VERSION 5.7 ;
BUSBITCHARS "[]" ;
DIVIDERCHAR "/" ;

PROPERTYDEFINITIONS
  MACRO CatenaDesignType STRING ;
END PROPERTYDEFINITIONS

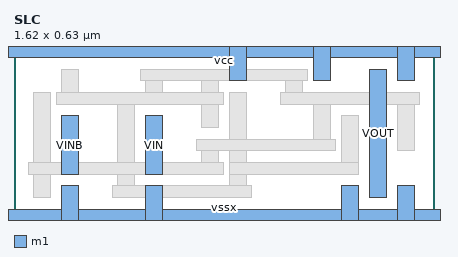
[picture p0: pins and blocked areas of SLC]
MACRO SLC
  CLASS CORE ;
  ORIGIN 0 0 ;
  FOREIGN SLC 0 0 ;
  SIZE 1.62 BY 0.63 ;
  SYMMETRY X Y ;
  SITE CoreSite ;
  PIN vssx
    DIRECTION INOUT ;
    USE GROUND ;
    SHAPE ABUTMENT ;
    PORT
      LAYER m1 ;
        RECT -0.034 -0.022 1.654 0.022 ;
        RECT 1.478 -0.022 1.546 0.112 ;
        RECT 1.262 -0.022 1.33 0.112 ;
        RECT 0.506 -0.022 0.574 0.112 ;
        RECT 0.182 -0.022 0.25 0.112 ;
    END
  END vssx
  PIN vcc
    DIRECTION INOUT ;
    USE POWER ;
    SHAPE ABUTMENT ;
    PORT
      LAYER m1 ;
        RECT -0.034 0.608 1.654 0.652 ;
        RECT 1.478 0.518 1.546 0.652 ;
        RECT 1.154 0.518 1.222 0.652 ;
        RECT 0.83 0.518 0.898 0.652 ;
    END
  END vcc
  PIN VOUT
    DIRECTION OUTPUT ;
    USE SIGNAL ;
    PORT
      LAYER m1 ;
        RECT 1.37 0.068 1.438 0.562 ;
    END
  END VOUT
  PIN VINB
    DIRECTION INPUT ;
    USE ANALOG ;
    PORT
      LAYER m1 ;
        RECT 0.182 0.158 0.25 0.382 ;
    END
  END VINB
  PIN VIN
    DIRECTION INPUT ;
    USE ANALOG ;
    PORT
      LAYER m1 ;
        RECT 0.506 0.158 0.574 0.382 ;
    END
  END VIN
  OBS
    LAYER m1 ;
      RECT 0.83 0.068 0.898 0.472 ;
      RECT 1.262 0.158 1.33 0.382 ;
      RECT 0.83 0.158 1.33 0.202 ;
      RECT 1.478 0.248 1.546 0.472 ;
      RECT 1.154 0.248 1.222 0.472 ;
      RECT 1.046 0.428 1.114 0.562 ;
      RECT 0.722 0.158 0.79 0.292 ;
      RECT 0.722 0.338 0.79 0.562 ;
      RECT 0.506 0.428 0.574 0.562 ;
      RECT 0.398 0.068 0.466 0.472 ;
      RECT 0.182 0.428 0.25 0.562 ;
      RECT 0.074 0.068 0.142 0.472 ;
    LAYER v1 ;
      RECT 1.482 0.428 1.542 0.472 ;
      RECT 1.158 0.248 1.218 0.292 ;
      RECT 1.05 0.428 1.11 0.472 ;
      RECT 1.05 0.518 1.11 0.562 ;
      RECT 0.834 0.068 0.894 0.112 ;
      RECT 0.726 0.158 0.786 0.202 ;
      RECT 0.726 0.248 0.786 0.292 ;
      RECT 0.726 0.428 0.786 0.472 ;
      RECT 0.51 0.518 0.57 0.562 ;
      RECT 0.402 0.068 0.462 0.112 ;
      RECT 0.186 0.428 0.246 0.472 ;
      RECT 0.078 0.158 0.138 0.202 ;
    LAYER m2 ;
      RECT 1.028 0.428 1.564 0.472 ;
      RECT 0.704 0.248 1.24 0.292 ;
      RECT 0.488 0.518 1.132 0.562 ;
      RECT 0.38 0.068 0.916 0.112 ;
      RECT 0.056 0.158 0.808 0.202 ;
      RECT 0.164 0.428 0.808 0.472 ;
  END
  PROPERTY CatenaDesignType "deviceLevel" ;
END SLC

END LIBRARY
